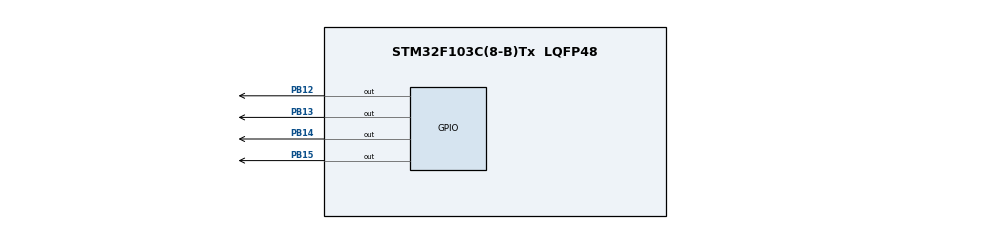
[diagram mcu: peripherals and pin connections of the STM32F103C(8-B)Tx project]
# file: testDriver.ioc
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Mcu.Family=STM32F1
Mcu.Name=STM32F103C(8-B)Tx
Mcu.Package=LQFP48
NVIC.PriorityGroup=NVIC_PRIORITYGROUP_4
PA13.Mode=Serial_Wire
PA13.Signal=SYS_JTMS-SWDIO
PA14.Mode=Serial_Wire
PA14.Signal=SYS_JTCK-SWCLK
PB12.Signal=GPIO_Output
PB13.Signal=GPIO_Output
PB14.Signal=GPIO_Output
PB15.Signal=GPIO_Output
PD0-OSC_IN.Mode=HSE-External-Oscillator
PD0-OSC_IN.Signal=RCC_OSC_IN
PD1-OSC_OUT.Mode=HSE-External-Oscillator
PD1-OSC_OUT.Signal=RCC_OSC_OUT
ProjectManager.HeapSize=0x200
ProjectManager.StackSize=0x400
ProjectManager.TargetToolchain=MDK-ARM V5.32
RCC.APB1Freq_Value=8000000
RCC.APB2Freq_Value=8000000
RCC.SYSCLKSource=RCC_SYSCLKSOURCE_PLLCLK
board=custom

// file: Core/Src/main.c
/* USER CODE BEGIN Header */
/**
  ******************************************************************************
  * @file           : main.c
  * @brief          : Main program body
  ******************************************************************************
  * @attention
  *
  * Copyright (c) 2022 STMicroelectronics.
  * All rights reserved.
  *
  * This software is licensed under terms that can be found in the LICENSE file
  * in the root directory of this software component.
  * If no LICENSE file comes with this software, it is provided AS-IS.
  *
  ******************************************************************************
  */

	#define BLUE_WIRE GPIO_PIN_12
	#define PINK_WIRE GPIO_PIN_13
	#define YELLOW_WIRE GPIO_PIN_14
	#define ORANGE_WIRE GPIO_PIN_15

	#define Q1 GPIO_PIN_11
	#define Q2 GPIO_PIN_10
	#define Q3 GPIO_PIN_1
	#define Q4 GPIO_PIN_0
	#define Q5 GPIO_PIN_7
	#define Q6 GPIO_PIN_6
/* USER CODE END Header */
#include "main.h"
#include "Coil_manager.h"
void doOneStep(int);
void doOtherStep(int);
void SimpleDirR(uint32_t delay);
void SimpleDirL(uint32_t delay);

void SystemClock_Config();
static void MX_GPIO_Init();

/* USER CODE BEGIN 0 */
int16_t State_Matrix [6][3] =
/*{+, -, N/C}*/ ///<- First, Second< third
{{1,-1,0},
 {1,0,-1},
 {0,1,-1},
 {-1,1,0},
 {-1,0,1},
 {0,-1,1},
};

/* USER CODE END 0 */

int main(void)
{

  /* MCU Configuration--------------------------------------------------------*/

  /* Reset of all peripherals, Initializes the Flash interface and the Systick. */
  HAL_Init();

  /* Configure the system clock */
  SystemClock_Config();

  /* Initialize all configured peripherals */
  MX_GPIO_Init();
  /* USER CODE BEGIN 2 */
	Connect_Disable_all_Coil();
  /* USER CODE END 2 */

  /* Infinite loop */
  /* USER CODE BEGIN WHILE */
  while (1)
  {
		/**Simple collector move*/
	 Connect_Coil1_Coil2_Coil3();
	 HAL_Delay(1);
	 Connect_Coil1_Coil3_Coil2();
	 HAL_Delay(1);
	 Connect_Coil2_Coil3_Coil1();
	 HAL_Delay(1);
	 Connect_Coil2_Coil1_Coil3();
	 HAL_Delay(1);
	 Connect_Coil3_Coil1_Coil2();
	 HAL_Delay(1);
	 Connect_Coil3_Coil2_Coil1();
	 HAL_Delay(1);
  }
  /* USER CODE END 3 */
}

void SimpleDirR(uint32_t delay){
	HAL_GPIO_WritePin(GPIOB,Q1,GPIO_PIN_SET);
	HAL_GPIO_WritePin(GPIOB,Q2,GPIO_PIN_RESET);
	HAL_Delay(delay);
	HAL_GPIO_WritePin(GPIOB,Q1,GPIO_PIN_RESET);
	HAL_GPIO_WritePin(GPIOB,Q2,GPIO_PIN_SET);
	HAL_Delay(delay);
	HAL_GPIO_WritePin(GPIOB,Q3,GPIO_PIN_SET);
	HAL_GPIO_WritePin(GPIOB,Q4,GPIO_PIN_RESET);
	HAL_Delay(delay);
	HAL_GPIO_WritePin(GPIOB,Q3,GPIO_PIN_RESET);
	HAL_GPIO_WritePin(GPIOB,Q4,GPIO_PIN_SET);
	HAL_Delay(delay);
	HAL_GPIO_WritePin(GPIOA,Q5,GPIO_PIN_SET);
	HAL_GPIO_WritePin(GPIOA,Q6,GPIO_PIN_RESET);
	HAL_Delay(delay);
	HAL_GPIO_WritePin(GPIOA,Q5,GPIO_PIN_RESET);
	HAL_GPIO_WritePin(GPIOA,Q6,GPIO_PIN_SET);
	HAL_Delay(delay);
}

void SimpleDirL(uint32_t delay){
	HAL_GPIO_WritePin(GPIOA,Q5,GPIO_PIN_SET);
	HAL_GPIO_WritePin(GPIOA,Q6,GPIO_PIN_RESET);
	HAL_Delay(delay);
	HAL_GPIO_WritePin(GPIOA,Q5,GPIO_PIN_RESET);
	HAL_GPIO_WritePin(GPIOA,Q6,GPIO_PIN_SET);
	HAL_Delay(delay);
	HAL_GPIO_WritePin(GPIOB,Q3,GPIO_PIN_SET);
	HAL_GPIO_WritePin(GPIOB,Q4,GPIO_PIN_RESET);
	HAL_Delay(delay);
	HAL_GPIO_WritePin(GPIOB,Q3,GPIO_PIN_RESET);
	HAL_GPIO_WritePin(GPIOB,Q4,GPIO_PIN_SET);
	HAL_Delay(delay);
	HAL_GPIO_WritePin(GPIOB,Q1,GPIO_PIN_SET);
	HAL_GPIO_WritePin(GPIOB,Q2,GPIO_PIN_RESET);
	HAL_Delay(delay);
	HAL_GPIO_WritePin(GPIOB,Q1,GPIO_PIN_RESET);
	HAL_GPIO_WritePin(GPIOB,Q2,GPIO_PIN_SET);
	HAL_Delay(delay);
}

void doOneStep(int timeDelay) {
    HAL_GPIO_WritePin(GPIOB, PINK_WIRE, GPIO_PIN_SET);
		HAL_GPIO_WritePin(GPIOB, YELLOW_WIRE, GPIO_PIN_SET);
		HAL_GPIO_WritePin(GPIOB, BLUE_WIRE, GPIO_PIN_RESET);
		HAL_GPIO_WritePin(GPIOB, ORANGE_WIRE, GPIO_PIN_RESET);
		HAL_Delay(timeDelay);
		HAL_GPIO_WritePin(GPIOB, PINK_WIRE, GPIO_PIN_RESET);
		HAL_GPIO_WritePin(GPIOB, YELLOW_WIRE, GPIO_PIN_RESET);
		HAL_GPIO_WritePin(GPIOB, BLUE_WIRE, GPIO_PIN_RESET);
		HAL_GPIO_WritePin(GPIOB, ORANGE_WIRE, GPIO_PIN_SET);
		HAL_Delay(timeDelay);
		HAL_GPIO_WritePin(GPIOB, PINK_WIRE, GPIO_PIN_RESET);
		HAL_GPIO_WritePin(GPIOB, YELLOW_WIRE, GPIO_PIN_SET);
		HAL_GPIO_WritePin(GPIOB, BLUE_WIRE, GPIO_PIN_RESET);
		HAL_GPIO_WritePin(GPIOB, ORANGE_WIRE, GPIO_PIN_RESET);
		HAL_Delay(timeDelay);
	  HAL_GPIO_WritePin(GPIOB, PINK_WIRE, GPIO_PIN_RESET);
		HAL_GPIO_WritePin(GPIOB, YELLOW_WIRE, GPIO_PIN_RESET);
		HAL_GPIO_WritePin(GPIOB, BLUE_WIRE, GPIO_PIN_SET);
		HAL_GPIO_WritePin(GPIOB, ORANGE_WIRE, GPIO_PIN_RESET);
		HAL_Delay(timeDelay);
}

void doOtherStep(int timeDelay) {
	  HAL_GPIO_WritePin(GPIOB, PINK_WIRE, GPIO_PIN_RESET);
		HAL_GPIO_WritePin(GPIOB, YELLOW_WIRE, GPIO_PIN_RESET);
		HAL_GPIO_WritePin(GPIOB, BLUE_WIRE, GPIO_PIN_SET);
		HAL_GPIO_WritePin(GPIOB, ORANGE_WIRE, GPIO_PIN_SET);
		HAL_Delay(timeDelay);
		HAL_GPIO_WritePin(GPIOB, PINK_WIRE, GPIO_PIN_RESET);
		HAL_GPIO_WritePin(GPIOB, YELLOW_WIRE, GPIO_PIN_SET);
		HAL_GPIO_WritePin(GPIOB, BLUE_WIRE, GPIO_PIN_RESET);
		HAL_GPIO_WritePin(GPIOB, ORANGE_WIRE, GPIO_PIN_RESET);
		HAL_Delay(timeDelay);
		HAL_GPIO_WritePin(GPIOB, PINK_WIRE, GPIO_PIN_RESET);
		HAL_GPIO_WritePin(GPIOB, YELLOW_WIRE, GPIO_PIN_RESET);
		HAL_GPIO_WritePin(GPIOB, BLUE_WIRE, GPIO_PIN_RESET);
		HAL_GPIO_WritePin(GPIOB, ORANGE_WIRE, GPIO_PIN_SET);
		HAL_Delay(timeDelay);
	  HAL_GPIO_WritePin(GPIOB, PINK_WIRE, GPIO_PIN_SET);
		HAL_GPIO_WritePin(GPIOB, YELLOW_WIRE, GPIO_PIN_RESET);
		HAL_GPIO_WritePin(GPIOB, BLUE_WIRE, GPIO_PIN_RESET);
		HAL_GPIO_WritePin(GPIOB, ORANGE_WIRE, GPIO_PIN_RESET);
		HAL_Delay(timeDelay);
}

void SystemClock_Config(void)
{
  RCC_OscInitTypeDef RCC_OscInitStruct = {0};
  RCC_ClkInitTypeDef RCC_ClkInitStruct = {0};

  /** Initializes the RCC Oscillators according to the specified parameters
  * in the RCC_OscInitTypeDef structure.
  */
  RCC_OscInitStruct.OscillatorType = RCC_OSCILLATORTYPE_HSI;
  RCC_OscInitStruct.HSIState = RCC_HSI_ON;
  RCC_OscInitStruct.HSICalibrationValue = RCC_HSICALIBRATION_DEFAULT;
  RCC_OscInitStruct.PLL.PLLState = RCC_PLL_ON;
  RCC_OscInitStruct.PLL.PLLSource = RCC_PLLSOURCE_HSI_DIV2;
  RCC_OscInitStruct.PLL.PLLMUL = RCC_PLL_MUL2;
  if (HAL_RCC_OscConfig(&RCC_OscInitStruct) != HAL_OK)
  {
    Error_Handler();
  }
  /** Initializes the CPU, AHB and APB buses clocks
  */
  RCC_ClkInitStruct.ClockType = RCC_CLOCKTYPE_HCLK|RCC_CLOCKTYPE_SYSCLK
                              |RCC_CLOCKTYPE_PCLK1|RCC_CLOCKTYPE_PCLK2;
  RCC_ClkInitStruct.SYSCLKSource = RCC_SYSCLKSOURCE_PLLCLK;
  RCC_ClkInitStruct.AHBCLKDivider = RCC_SYSCLK_DIV1;
  RCC_ClkInitStruct.APB1CLKDivider = RCC_HCLK_DIV1;
  RCC_ClkInitStruct.APB2CLKDivider = RCC_HCLK_DIV1;

  if (HAL_RCC_ClockConfig(&RCC_ClkInitStruct, FLASH_LATENCY_0) != HAL_OK)
  {
    Error_Handler();
  }
}

static void MX_GPIO_Init(void)
{
  GPIO_InitTypeDef GPIO_InitStruct = {0};

  /* GPIO Ports Clock Enable */
  __HAL_RCC_GPIOD_CLK_ENABLE();
  __HAL_RCC_GPIOB_CLK_ENABLE();
  __HAL_RCC_GPIOA_CLK_ENABLE();
  __HAL_RCC_GPIOC_CLK_ENABLE();

  /*Configure GPIO pin Output Level */
  HAL_GPIO_WritePin(GPIOB, GPIO_PIN_12|GPIO_PIN_13|GPIO_PIN_14|GPIO_PIN_15|GPIO_PIN_11|GPIO_PIN_10|GPIO_PIN_1|GPIO_PIN_0, GPIO_PIN_RESET);
  HAL_GPIO_WritePin(GPIOC, GPIO_PIN_13, GPIO_PIN_RESET);
	HAL_GPIO_WritePin(GPIOA, GPIO_PIN_6|GPIO_PIN_7, GPIO_PIN_RESET);

  /*Configure GPIO pins : PB12 PB13 PB14 PB15 */
  GPIO_InitStruct.Pin = GPIO_PIN_12|GPIO_PIN_13|GPIO_PIN_14|GPIO_PIN_15|GPIO_PIN_11|GPIO_PIN_10|GPIO_PIN_1|GPIO_PIN_0;
  GPIO_InitStruct.Mode = GPIO_MODE_OUTPUT_PP;
  GPIO_InitStruct.Pull = GPIO_NOPULL;
  GPIO_InitStruct.Speed = GPIO_SPEED_FREQ_LOW;
  HAL_GPIO_Init(GPIOB, &GPIO_InitStruct);

	  /*Configure GPIO pins : A7 A6*/
  GPIO_InitStruct.Pin = GPIO_PIN_7|GPIO_PIN_6;
  GPIO_InitStruct.Mode = GPIO_MODE_OUTPUT_PP;
  GPIO_InitStruct.Pull = GPIO_NOPULL;
  GPIO_InitStruct.Speed = GPIO_SPEED_FREQ_LOW;
  HAL_GPIO_Init(GPIOA, &GPIO_InitStruct);

	 /*Configure GPIO pins : PC13  */
  GPIO_InitStruct.Pin = GPIO_PIN_13;
  GPIO_InitStruct.Mode = GPIO_MODE_OUTPUT_PP;
  GPIO_InitStruct.Pull = GPIO_PULLUP;
  GPIO_InitStruct.Speed = GPIO_SPEED_FREQ_LOW;
  HAL_GPIO_Init(GPIOC, &GPIO_InitStruct);

}

void Error_Handler(void)
{
  __disable_irq();
  while (1)
  {
  }
}
